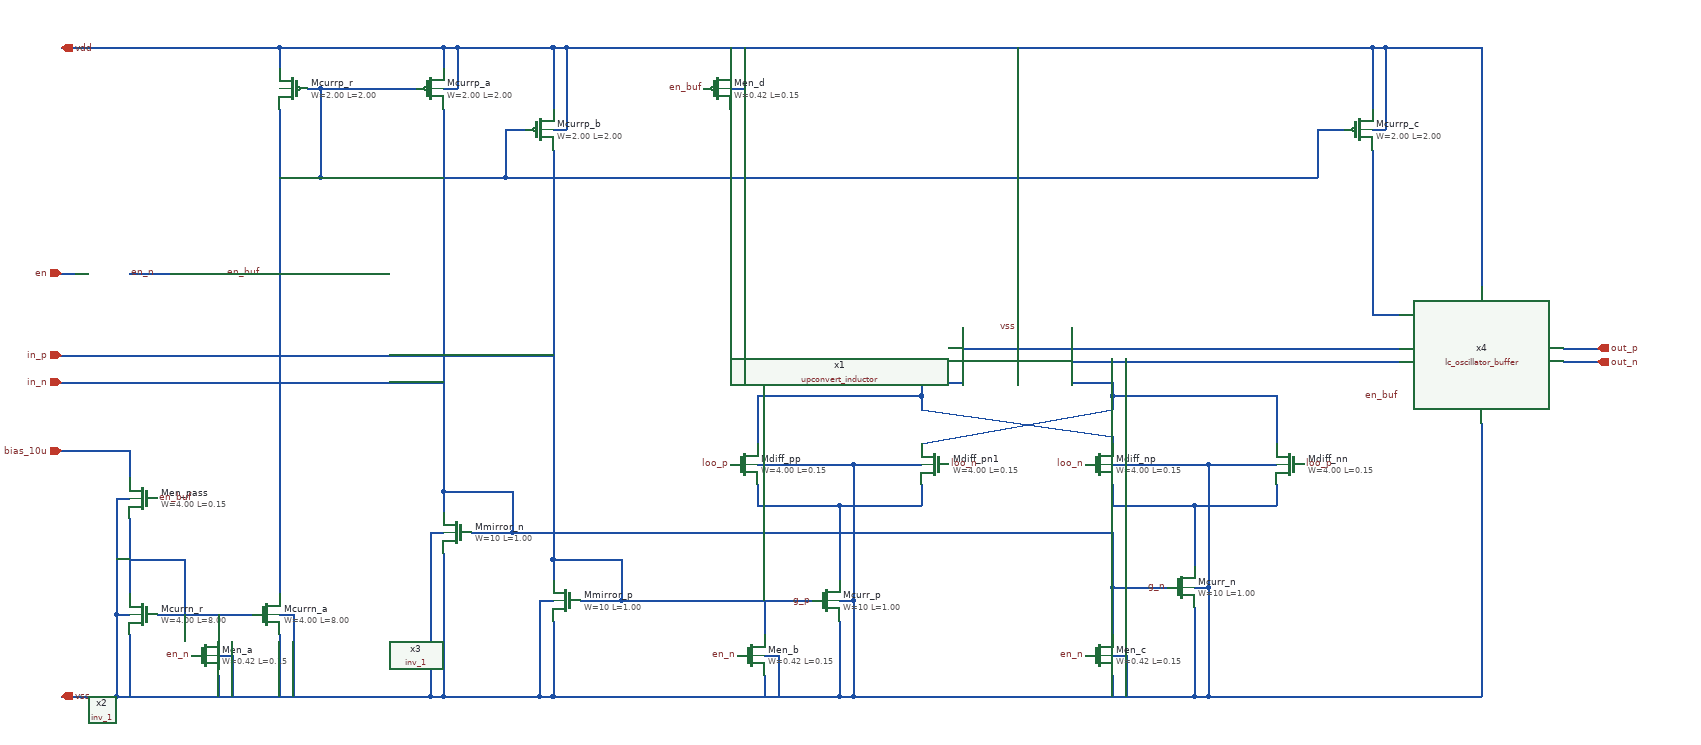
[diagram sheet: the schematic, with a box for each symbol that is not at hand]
v {xschem version=2.9.9 file_version=1.2 }
G {}
K {}
V {}
S {}
E {}
N 1020 -310 1020 -280 { lab=#net1}
N 1140 -280 1260 -280 { lab=#net1}
N 1260 -310 1260 -280 { lab=#net1}
N 1140 -280 1140 -170 { lab=#net1}
N 1160 -340 1260 -340 { lab=vss}
N 1160 -140 1160 0 { lab=vss}
N 1140 -110 1140 0 { lab=vss}
N 1140 -140 1160 -140 { lab=vss}
N 1540 -310 1540 -280 { lab=#net2}
N 1660 -280 1780 -280 { lab=#net2}
N 1780 -310 1780 -280 { lab=#net2}
N 1660 -280 1660 -190 { lab=#net2}
N 1680 -340 1780 -340 { lab=vss}
N 1680 -160 1680 0 { lab=vss}
N 1660 -130 1660 0 { lab=vss}
N 1660 -160 1680 -160 { lab=vss}
N 820 -140 1100 -140 { lab=g_p}
N 700 -140 720 -140 { lab=vss}
N 700 -140 700 0 { lab=vss}
N 720 -110 720 0 { lab=vss}
N 720 -200 720 -170 { lab=g_p}
N 720 -200 820 -200 { lab=g_p}
N 820 -200 820 -140 { lab=g_p}
N 660 -240 1540 -240 { lab=g_n}
N 1540 -240 1540 -160 { lab=g_n}
N 1540 -160 1620 -160 { lab=g_n}
N 560 -300 560 -270 { lab=g_n}
N 560 -300 660 -300 { lab=g_n}
N 660 -300 660 -240 { lab=g_n}
N 560 -210 560 0 { lab=vss}
N 540 -240 560 -240 { lab=vss}
N 540 -240 540 0 { lab=vss}
N 1660 0 1680 0 { lab=vss}
N 1780 -440 1780 -370 { lab=#net3}
N 1020 -440 1020 -370 { lab=#net4}
N 1540 -440 1540 -420 { lab=#net3}
N 1260 -440 1260 -420 { lab=#net4}
N 420 0 540 0 { lab=vss}
N 1020 -280 1140 -280 { lab=#net1}
N 1020 -340 1160 -340 { lab=vss}
N 1140 0 1160 0 { lab=vss}
N 720 0 1140 0 { lab=vss}
N 1160 -340 1160 -140 { lab=vss}
N 1540 -280 1660 -280 { lab=#net2}
N 1540 -340 1680 -340 { lab=vss}
N 1160 0 1660 0 { lab=vss}
N 1680 -340 1680 -160 { lab=vss}
N 560 0 700 0 { lab=vss}
N 700 0 720 0 { lab=vss}
N 760 -140 820 -140 { lab=g_p}
N 600 -240 660 -240 { lab=g_n}
N 540 0 560 0 { lab=vss}
N 1540 -440 1780 -440 { lab=#net3}
N 1020 -440 1260 -440 { lab=#net4}
N 1480 -540 1480 -460 { lab=#net3}
N 1480 -460 1540 -460 { lab=#net3}
N 1540 -460 1540 -440 { lab=#net3}
N 1320 -540 1320 -460 { lab=#net4}
N 1260 -460 1320 -460 { lab=#net4}
N 1260 -460 1260 -440 { lab=#net4}
N 580 -950 720 -950 { lab=vdd}
N 320 -950 560 -950 { lab=vdd}
N 2080 -400 2080 -280 { lab=vss}
N 1920 -560 1960 -560 { lab=#net5}
N 1920 -600 1920 -560 { lab=#net5}
N 2200 -510 2250 -510 { lab=out_p}
N 2200 -490 2250 -490 { lab=out_n}
N 720 -800 720 -200 { lab=g_p}
N 720 -830 740 -830 { lab=vdd}
N 740 -950 740 -830 { lab=vdd}
N 720 -950 720 -860 { lab=vdd}
N 560 -890 580 -890 { lab=vdd}
N 580 -950 580 -890 { lab=vdd}
N 560 -950 560 -920 { lab=vdd}
N 320 -860 320 -830 { lab=#net6}
N 380 -890 520 -890 { lab=#net6}
N 320 -950 320 -920 { lab=vdd}
N 380 -890 380 -830 { lab=#net6}
N 720 -950 740 -950 { lab=vdd}
N 560 -950 580 -950 { lab=vdd}
N 260 -950 320 -950 { lab=vdd}
N 360 -890 380 -890 { lab=#net6}
N 560 -860 560 -300 { lab=g_n}
N 320 -830 320 -150 { lab=#net6}
N 80 -120 100 -120 { lab=vss}
N 80 -120 80 0 { lab=vss}
N 80 0 420 0 { lab=vss}
N 320 -90 320 0 { lab=vss}
N 320 -120 340 -120 { lab=vss}
N 340 -120 340 0 { lab=vss}
N 100 -90 100 0 { lab=vss}
N 140 -120 280 -120 { lab=#net7}
N 100 -220 100 -150 { lab=#net7}
N 0 -460 560 -460 { lab=in_n}
N 0 -500 720 -500 { lab=in_p}
N 320 -760 380 -760 { lab=#net6}
N 380 -820 380 -760 { lab=#net6}
N 380 -830 380 -820 { lab=#net6}
N 380 -760 650 -760 { lab=#net6}
N 650 -830 650 -760 { lab=#net6}
N 650 -830 680 -830 { lab=#net6}
N 1920 -830 1940 -830 { lab=vdd}
N 1940 -950 1940 -830 { lab=vdd}
N 1920 -950 1920 -860 { lab=vdd}
N 1920 -950 1940 -950 { lab=vdd}
N 1840 -830 1840 -760 { lab=#net6}
N 1840 -830 1880 -830 { lab=#net6}
N 650 -760 1840 -760 { lab=#net6}
N 1540 -380 1540 -370 { lab=#net4}
N 1260 -420 1540 -380 { lab=#net4}
N 1260 -370 1540 -420 { lab=#net3}
N 1480 -490 1960 -490 { lab=#net3}
N 1320 -510 1960 -510 { lab=#net4}
N 1920 -800 1920 -600 { lab=#net5}
N 740 -950 1920 -950 { lab=vdd}
N 1400 -950 1400 -740 { lab=vdd}
N 2080 -940 2080 -600 { lab=vdd}
N 2080 -950 2080 -940 { lab=vdd}
N 1940 -950 2080 -950 { lab=vdd}
N 2080 -280 2080 0 { lab=vss}
N 1680 0 2080 0 { lab=vss}
N 80 -290 100 -290 { lab=vss}
N 80 -290 80 -120 { lab=vss}
N 100 -260 100 -220 { lab=#net7}
N 0 -360 100 -360 { lab=bias_10u}
N 100 -360 100 -320 { lab=bias_10u}
N 100 -200 180 -200 { lab=#net7}
N 180 -200 180 -120 { lab=#net7}
N 230 -120 230 -90 { lab=#net7}
N 230 -30 230 0 { lab=vss}
N 230 -60 250 -60 { lab=vss}
N 250 -60 250 0 { lab=vss}
N 1030 -30 1030 0 { lab=vss}
N 1030 -60 1050 -60 { lab=vss}
N 1050 -60 1050 0 { lab=vss}
N 1540 -30 1540 0 { lab=vss}
N 1540 -60 1560 -60 { lab=vss}
N 1560 -60 1560 0 { lab=vss}
N 1030 -140 1030 -90 { lab=g_p}
N 1540 -160 1540 -90 { lab=g_n}
N 980 -950 980 -920 { lab=vdd}
N 980 -890 1000 -890 { lab=vdd}
N 1000 -950 1000 -890 { lab=vdd}
N 980 -860 980 -760 { lab=#net6}
N -0 0 80 -0 { lab=vss}
N 0 -950 260 -950 { lab=vdd}
N 100 -620 160 -620 { lab=en_n}
N -0 -620 20 -620 { lab=en}
C {sky130_fd_pr/nfet_01v8_lvt.sym} 1120 -140 0 0 {name=Mcurr_p
L=1.00
W=10
nf=2
mult=8
ad="'int((nf+1)/2) * W/nf * 0.29'" 
pd="'2*int((nf+1)/2) * (W/nf + 0.29)'"
as="'int((nf+2)/2) * W/nf * 0.29'" 
ps="'2*int((nf+2)/2) * (W/nf + 0.29)'"
nrd="'0.29 / W'" nrs="'0.29 / W'"
sa=0 sb=0 sd=0
model=nfet_01v8_lvt
spiceprefix=X
}
C {sky130_fd_pr/nfet_01v8_lvt.sym} 1000 -340 0 0 {name=Mdiff_pp
L=0.15
W=4.00
nf=1
mult=2
ad="'int((nf+1)/2) * W/nf * 0.29'" 
pd="'2*int((nf+1)/2) * (W/nf + 0.29)'"
as="'int((nf+2)/2) * W/nf * 0.29'" 
ps="'2*int((nf+2)/2) * (W/nf + 0.29)'"
nrd="'0.29 / W'" nrs="'0.29 / W'"
sa=0 sb=0 sd=0
model=nfet_01v8_lvt
spiceprefix=X
}
C {sky130_fd_pr/nfet_01v8_lvt.sym} 1280 -340 0 1 {name=Mdiff_pn1
L=0.15
W=4.00
nf=1
mult=2
ad="'int((nf+1)/2) * W/nf * 0.29'" 
pd="'2*int((nf+1)/2) * (W/nf + 0.29)'"
as="'int((nf+2)/2) * W/nf * 0.29'" 
ps="'2*int((nf+2)/2) * (W/nf + 0.29)'"
nrd="'0.29 / W'" nrs="'0.29 / W'"
sa=0 sb=0 sd=0
model=nfet_01v8_lvt
spiceprefix=X
}
C {sky130_fd_pr/nfet_01v8_lvt.sym} 1640 -160 0 0 {name=Mcurr_n
L=1.00
W=10
nf=2
mult=8
ad="'int((nf+1)/2) * W/nf * 0.29'" 
pd="'2*int((nf+1)/2) * (W/nf + 0.29)'"
as="'int((nf+2)/2) * W/nf * 0.29'" 
ps="'2*int((nf+2)/2) * (W/nf + 0.29)'"
nrd="'0.29 / W'" nrs="'0.29 / W'"
sa=0 sb=0 sd=0
model=nfet_01v8_lvt
spiceprefix=X
}
C {sky130_fd_pr/nfet_01v8_lvt.sym} 1520 -340 0 0 {name=Mdiff_np
L=0.15
W=4.00
nf=1
mult=2
ad="'int((nf+1)/2) * W/nf * 0.29'" 
pd="'2*int((nf+1)/2) * (W/nf + 0.29)'"
as="'int((nf+2)/2) * W/nf * 0.29'" 
ps="'2*int((nf+2)/2) * (W/nf + 0.29)'"
nrd="'0.29 / W'" nrs="'0.29 / W'"
sa=0 sb=0 sd=0
model=nfet_01v8_lvt
spiceprefix=X
}
C {sky130_fd_pr/nfet_01v8_lvt.sym} 1800 -340 0 1 {name=Mdiff_nn
L=0.15
W=4.00
nf=1
mult=2
ad="'int((nf+1)/2) * W/nf * 0.29'" 
pd="'2*int((nf+1)/2) * (W/nf + 0.29)'"
as="'int((nf+2)/2) * W/nf * 0.29'" 
ps="'2*int((nf+2)/2) * (W/nf + 0.29)'"
nrd="'0.29 / W'" nrs="'0.29 / W'"
sa=0 sb=0 sd=0
model=nfet_01v8_lvt
spiceprefix=X
}
C {sky130_fd_pr/nfet_01v8_lvt.sym} 580 -240 0 1 {name=Mmirror_n
L=1.00
W=10
nf=2
mult=2
ad="'int((nf+1)/2) * W/nf * 0.29'" 
pd="'2*int((nf+1)/2) * (W/nf + 0.29)'"
as="'int((nf+2)/2) * W/nf * 0.29'" 
ps="'2*int((nf+2)/2) * (W/nf + 0.29)'"
nrd="'0.29 / W'" nrs="'0.29 / W'"
sa=0 sb=0 sd=0
model=nfet_01v8_lvt
spiceprefix=X
}
C {sky130_fd_pr/nfet_01v8_lvt.sym} 740 -140 0 1 {name=Mmirror_p
L=1.00
W=10
nf=2
mult=2
ad="'int((nf+1)/2) * W/nf * 0.29'" 
pd="'2*int((nf+1)/2) * (W/nf + 0.29)'"
as="'int((nf+2)/2) * W/nf * 0.29'" 
ps="'2*int((nf+2)/2) * (W/nf + 0.29)'"
nrd="'0.29 / W'" nrs="'0.29 / W'"
sa=0 sb=0 sd=0
model=nfet_01v8_lvt
spiceprefix=X
}
C {lab_wire.sym} 1100 -140 0 0 {name=l11 sig_type=std_logic lab=g_p}
C {lab_wire.sym} 1620 -160 0 0 {name=l10 sig_type=std_logic lab=g_n}
C {upconvert_inductor/upconvert_inductor.sym} 1400 -640 0 1 {name=x1}
C {lab_wire.sym} 1300 -340 0 1 {name=l1 sig_type=std_logic lab=loo_n}
C {lab_wire.sym} 1500 -340 0 0 {name=l3 sig_type=std_logic lab=loo_n}
C {lab_wire.sym} 1820 -340 0 1 {name=l4 sig_type=std_logic lab=loo_p}
C {lab_wire.sym} 980 -340 0 0 {name=l2 sig_type=std_logic lab=loo_p}
C {lc_oscillator_buffer/lc_oscillator_buffer.sym} 2080 -500 0 0 {name=x4}
C {sky130_fd_pr/nfet_01v8_lvt.sym} 120 -120 0 1 {name=Mcurrn_r
L=8.00
W=4.00
nf=1
mult=2
ad="'int((nf+1)/2) * W/nf * 0.29'" 
pd="'2*int((nf+1)/2) * (W/nf + 0.29)'"
as="'int((nf+2)/2) * W/nf * 0.29'" 
ps="'2*int((nf+2)/2) * (W/nf + 0.29)'"
nrd="'0.29 / W'" nrs="'0.29 / W'"
sa=0 sb=0 sd=0
model=nfet_01v8_lvt
spiceprefix=X
}
C {sky130_fd_pr/nfet_01v8_lvt.sym} 300 -120 0 0 {name=Mcurrn_a
L=8.00
W=4.00
nf=1
mult=2
ad="'int((nf+1)/2) * W/nf * 0.29'" 
pd="'2*int((nf+1)/2) * (W/nf + 0.29)'"
as="'int((nf+2)/2) * W/nf * 0.29'" 
ps="'2*int((nf+2)/2) * (W/nf + 0.29)'"
nrd="'0.29 / W'" nrs="'0.29 / W'"
sa=0 sb=0 sd=0
model=nfet_01v8_lvt
spiceprefix=X
}
C {ipin.sym} 0 -460 0 0 {name=p1 lab=in_n}
C {ipin.sym} 0 -500 0 0 {name=p2 lab=in_p}
C {sky130_fd_pr/pfet_01v8_lvt.sym} 340 -890 0 1 {name=Mcurrp_r
L=2.00
W=2.00
nf=1
mult=2
ad="'int((nf+1)/2) * W/nf * 0.29'" 
pd="'2*int((nf+1)/2) * (W/nf + 0.29)'"
as="'int((nf+2)/2) * W/nf * 0.29'" 
ps="'2*int((nf+2)/2) * (W/nf + 0.29)'"
nrd="'0.29 / W'" nrs="'0.29 / W'"
sa=0 sb=0 sd=0
model=pfet_01v8_lvt
spiceprefix=X
}
C {sky130_fd_pr/pfet_01v8_lvt.sym} 540 -890 0 0 {name=Mcurrp_a
L=2.00
W=2.00
nf=1
mult=20
ad="'int((nf+1)/2) * W/nf * 0.29'" 
pd="'2*int((nf+1)/2) * (W/nf + 0.29)'"
as="'int((nf+2)/2) * W/nf * 0.29'" 
ps="'2*int((nf+2)/2) * (W/nf + 0.29)'"
nrd="'0.29 / W'" nrs="'0.29 / W'"
sa=0 sb=0 sd=0
model=pfet_01v8_lvt
spiceprefix=X
}
C {sky130_fd_pr/pfet_01v8_lvt.sym} 700 -830 0 0 {name=Mcurrp_b
L=2.00
W=2.00
nf=1
mult=20
ad="'int((nf+1)/2) * W/nf * 0.29'" 
pd="'2*int((nf+1)/2) * (W/nf + 0.29)'"
as="'int((nf+2)/2) * W/nf * 0.29'" 
ps="'2*int((nf+2)/2) * (W/nf + 0.29)'"
nrd="'0.29 / W'" nrs="'0.29 / W'"
sa=0 sb=0 sd=0
model=pfet_01v8_lvt
spiceprefix=X
}
C {ipin.sym} 0 -360 0 0 {name=p3 lab=bias_10u}
C {sky130_fd_pr/pfet_01v8_lvt.sym} 1900 -830 0 0 {name=Mcurrp_c
L=2.00
W=2.00
nf=1
mult=4
ad="'int((nf+1)/2) * W/nf * 0.29'" 
pd="'2*int((nf+1)/2) * (W/nf + 0.29)'"
as="'int((nf+2)/2) * W/nf * 0.29'" 
ps="'2*int((nf+2)/2) * (W/nf + 0.29)'"
nrd="'0.29 / W'" nrs="'0.29 / W'"
sa=0 sb=0 sd=0
model=pfet_01v8_lvt
spiceprefix=X
}
C {lab_wire.sym} 1400 -540 2 1 {name=l5 sig_type=std_logic lab=vss}
C {sky130_fd_pr/nfet_01v8.sym} 210 -60 0 0 {name=Men_a
L=0.15
W=0.42
nf=1 
mult=1
ad="'int((nf+1)/2) * W/nf * 0.29'" 
pd="'2*int((nf+1)/2) * (W/nf + 0.29)'"
as="'int((nf+2)/2) * W/nf * 0.29'" 
ps="'2*int((nf+2)/2) * (W/nf + 0.29)'"
nrd="'0.29 / W'" nrs="'0.29 / W'"
sa=0 sb=0 sd=0
model=nfet_01v8
spiceprefix=X
}
C {sky130_fd_pr/nfet_01v8_lvt.sym} 120 -290 0 1 {name=Men_pass
L=0.15
W=4.00
nf=1
mult=2
ad="'int((nf+1)/2) * W/nf * 0.29'" 
pd="'2*int((nf+1)/2) * (W/nf + 0.29)'"
as="'int((nf+2)/2) * W/nf * 0.29'" 
ps="'2*int((nf+2)/2) * (W/nf + 0.29)'"
nrd="'0.29 / W'" nrs="'0.29 / W'"
sa=0 sb=0 sd=0
model=nfet_01v8_lvt
spiceprefix=X
}
C {lab_pin.sym} 140 -290 0 1 {name=l7 sig_type=std_logic lab=en_buf}
C {lab_pin.sym} 190 -60 0 0 {name=l6 sig_type=std_logic lab=en_n}
C {sky130_fd_pr/nfet_01v8.sym} 1010 -60 0 0 {name=Men_b
L=0.15
W=0.42
nf=1 
mult=1
ad="'int((nf+1)/2) * W/nf * 0.29'" 
pd="'2*int((nf+1)/2) * (W/nf + 0.29)'"
as="'int((nf+2)/2) * W/nf * 0.29'" 
ps="'2*int((nf+2)/2) * (W/nf + 0.29)'"
nrd="'0.29 / W'" nrs="'0.29 / W'"
sa=0 sb=0 sd=0
model=nfet_01v8
spiceprefix=X
}
C {lab_pin.sym} 990 -60 0 0 {name=l8 sig_type=std_logic lab=en_n}
C {sky130_fd_pr/nfet_01v8.sym} 1520 -60 0 0 {name=Men_c
L=0.15
W=0.42
nf=1 
mult=1
ad="'int((nf+1)/2) * W/nf * 0.29'" 
pd="'2*int((nf+1)/2) * (W/nf + 0.29)'"
as="'int((nf+2)/2) * W/nf * 0.29'" 
ps="'2*int((nf+2)/2) * (W/nf + 0.29)'"
nrd="'0.29 / W'" nrs="'0.29 / W'"
sa=0 sb=0 sd=0
model=nfet_01v8
spiceprefix=X
}
C {lab_pin.sym} 1500 -60 0 0 {name=l9 sig_type=std_logic lab=en_n}
C {sky130_fd_pr/pfet_01v8.sym} 960 -890 0 0 {name=Men_d
L=0.15
W=0.42
nf=1
mult=1
ad="'int((nf+1)/2) * W/nf * 0.29'" 
pd="'2*int((nf+1)/2) * (W/nf + 0.29)'"
as="'int((nf+2)/2) * W/nf * 0.29'" 
ps="'2*int((nf+2)/2) * (W/nf + 0.29)'"
nrd="'0.29 / W'" nrs="'0.29 / W'"
sa=0 sb=0 sd=0
model=pfet_01v8
spiceprefix=X
}
C {lab_pin.sym} 940 -890 0 0 {name=l12 sig_type=std_logic lab=en_buf}
C {iopin.sym} 0 0 0 1 {name=p4 lab=vss}
C {iopin.sym} 0 -950 0 1 {name=p5 lab=vdd}
C {opin.sym} 2250 -510 0 0 {name=p6 lab=out_p}
C {opin.sym} 2250 -490 0 0 {name=p7 lab=out_n}
C {sky130_stdcells/inv_1.sym} 60 -620 0 0 {name=x2 VGND=vss VNB=vss VPB=vdd VPWR=vdd prefix=sky130_fd_sc_hd__ }
C {lab_wire.sym} 100 -620 0 1 {name=l13 sig_type=std_logic lab=en_n}
C {lab_wire.sym} 240 -620 0 1 {name=l14 sig_type=std_logic lab=en_buf}
C {ipin.sym} 0 -620 0 0 {name=p8 lab=en}
C {sky130_stdcells/inv_1.sym} 200 -620 0 0 {name=x3 VGND=vss VNB=vss VPB=vdd VPWR=vdd prefix=sky130_fd_sc_hd__ }
C {lab_wire.sym} 1960 -440 0 0 {name=l15 sig_type=std_logic lab=en_buf}
